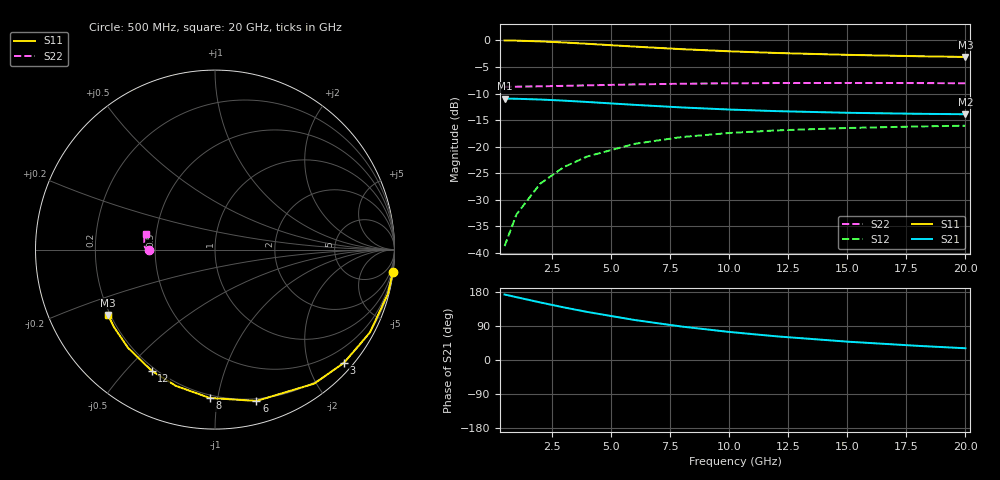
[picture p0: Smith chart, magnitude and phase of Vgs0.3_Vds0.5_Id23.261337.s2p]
# Hz S RI R 50
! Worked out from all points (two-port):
!   12 points, 500 MHz to 20 GHz, reference 50 ohm
!   highest |S21| = -10.94 dB at 500 MHz (marker M1); lowest = -13.9 dB at 20 GHz (marker M2)
!   |S21| within 3 dB of the highest: start of sweep to end of sweep
!   lowest |S11| = -3.1 dB at 20 GHz (marker M3), VSWR 5.64, Z = 9.55 - j13.6 ohm
!   |S11| at or under -10 dB: nowhere
!   |S22| runs from -8.7 to -8.0 dB; largest |S21 - S12| = 0.28
!   S11 on the Smith chart (normalised r, x): 500 MHz: 0, -16; 3 GHz: 0.18, -2.64; 6 GHz: 0.18, -1.29; 8 GHz: 0.18, -0.95; 12 GHz: 0.18, -0.59; 20 GHz: 0.19, -0.27
5e8  0.9908 -0.1245  -0.2815 0.0352  0.000902 0.0116  -0.3665 -0.00104
1e9  0.9638 -0.2452  -0.2738 0.0693  0.00355 0.0228  -0.3672 -0.00198
2e9  0.8632 -0.4618  -0.2454 0.1305  0.0134 0.0427  -0.3698 -0.00316
3e9  0.7186 -0.6307  -0.2046 0.1782  0.0276 0.058  -0.3735 -0.00302
4e9  0.5532 -0.7467  -0.1578 0.211  0.0438 0.0681  -0.3777 -0.00145
6e9  0.2307 -0.8433  -0.0665 0.2385  0.0755 0.075  -0.3854 0.0055
8e9  -0.0291 -0.8265  0.00727 0.234  0.101 0.0708  -0.3909 0.0155
1e10  -0.2185 -0.7591  0.0613 0.2152  0.1197 0.0616  -0.394 0.027
1.2e10  -0.3525 -0.6752  0.1 0.1916  0.133 0.0508  -0.3951 0.0389
1.5e10  -0.4836 -0.5485  0.1384 0.156  0.146 0.0343  -0.3938 0.0566
1.8e10  -0.5619 -0.4336  0.1623 0.1236  0.1539 0.0189  -0.3899 0.074
2e10  -0.5958 -0.3649  0.1732 0.1041  0.1574 0.00933  -0.3861 0.0852
